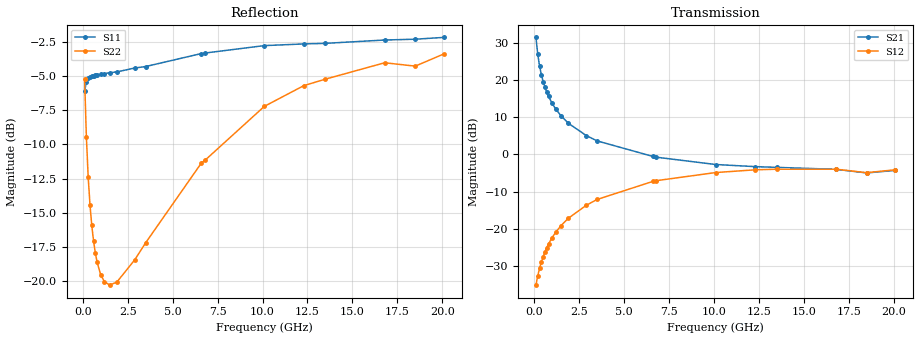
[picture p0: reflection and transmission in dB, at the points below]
!  Infineon Technologies AG
! BFR380L3 , PF131585-7, No.6, Th 09.10.01, soldered on pcb-board, measured with PP GSG850
!  Vce=3.5 V,  Ic=80.0 mA
! Common Emitter S-Parameters:  15. November 2001
#  GHz  S  MA  R  50
! f  S11  S21  S12  S22
! GHz  Mag  Ang  Mag  Ang  Mag  Ang  Mag  Ang
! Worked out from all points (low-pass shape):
!   201 points, 100 MHz to 20.1 GHz, reference 50 ohm
!   highest |S21| = 31.39 dB at 100 MHz (marker M1); lowest = -5.0 dB at 18.5 GHz (marker M2)
!   |S21| within 3 dB of the highest: start of sweep to 166.9 MHz
!   lowest |S11| = -6.1 dB at 100 MHz (marker M3), VSWR 2.96, Z = 22.7 - j27 ohm
!   |S11| at or under -10 dB: nowhere
!   |S22| runs from -20.3 to -3.4 dB; largest |S21 - S12| = 37
!   S11 on the Smith chart (normalised r, x): 100 MHz: 0.45, -0.54; 500 MHz: 0.28, -0.07; 2.9 GHz: 0.27, +0.31; 6.6 GHz: 0.31, +0.78; 12.3 GHz: 0.52, +1.51; 20.1 GHz: 1.06, +2.57
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0.1  0.495 -114.9  37.12 128.2  0.01762 59.3  0.5508 -50.4
0.2  0.5368 -144.7  22.14 109.4  0.02339 56.5  0.3364 -67.9
0.3  0.5526 -158.2  15.42 101.0  0.02969 60.8  0.2406 -75.4
0.4  0.5566 -165.7  11.77 95.7  0.03575 63.4  0.19 -80.0
0.5  0.5622 -171.1  9.499 91.9  0.04245 66.1  0.1596 -83.3
0.6  0.5647 -175.0  7.956 88.9  0.04922 67.6  0.1399 -86.0
0.7  0.5671 -178.4  6.854 86.2  0.0558 68.7  0.1264 -88.5
0.8  0.5688 178.7  6.016 83.8  0.06273 69.5  0.1168 -90.8
1  0.5706 173.9  4.844 79.6  0.07637 70.3  0.1051 -95.2
1.2  0.5748 169.9  4.06 75.8  0.0902 70.3  0.09945 -99.7
1.5  0.5788 164.2  3.276 70.5  0.111 69.8  0.0965 -106.1
1.9  0.5831 157.6  2.621 64.1  0.1389 68.3  0.0991 -114.9
2.9  0.6025 142.9  1.788 49.6  0.2074 62.8  0.1197 -135.6
3.5  0.61 134.7  1.518 41.8  0.2483 58.9  0.138 -144.8
6.6  0.6806 100.7  0.9395 11.3  0.4336 36.7  0.2703 167.0
6.8  0.6835 98.8  0.9169 9.9  0.4441 35.1  0.2766 164.3
10.1  0.7277 74.2  0.7313 -8.4  0.5704 12.2  0.4358 128.9
12.3  0.7381 62.7  0.6848 -17.2  0.621 -2.1  0.5193 108.5
13.5  0.7417 57.1  0.6698 -22.0  0.6325 -9.4  0.5484 99.4
16.8  0.7629 45.9  0.6301 -32.7  0.6326 -25.6  0.6297 77.3
18.5  0.7681 44.2  0.5639 -39.7  0.5681 -33.8  0.612 71.8
20.1  0.78 37.3  0.6093 -43.6  0.6217 -39.2  0.6788 60.8
